VERSION 5.7 ;
BUSBITCHARS "[]" ;
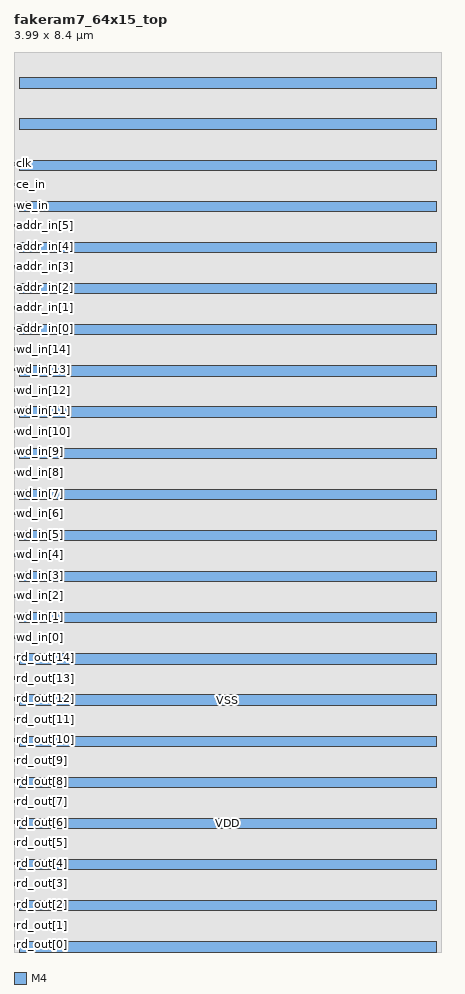
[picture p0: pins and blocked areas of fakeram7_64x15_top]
MACRO fakeram7_64x15_top
  FOREIGN fakeram7_64x15_top 0 0 ;
  SYMMETRY X Y R90 ;
  SIZE 3.990 BY 8.400 ;
  CLASS BLOCK ;
  PIN rd_out[0]
    DIRECTION OUTPUT ;
    USE SIGNAL ;
    SHAPE ABUTMENT ;
    PORT
      LAYER M4 ;
      RECT 0.000 0.048 0.024 0.072 ;
    END
  END rd_out[0]
  PIN rd_out[1]
    DIRECTION OUTPUT ;
    USE SIGNAL ;
    SHAPE ABUTMENT ;
    PORT
      LAYER M4 ;
      RECT 0.000 0.240 0.024 0.264 ;
    END
  END rd_out[1]
  PIN rd_out[2]
    DIRECTION OUTPUT ;
    USE SIGNAL ;
    SHAPE ABUTMENT ;
    PORT
      LAYER M4 ;
      RECT 0.000 0.432 0.024 0.456 ;
    END
  END rd_out[2]
  PIN rd_out[3]
    DIRECTION OUTPUT ;
    USE SIGNAL ;
    SHAPE ABUTMENT ;
    PORT
      LAYER M4 ;
      RECT 0.000 0.624 0.024 0.648 ;
    END
  END rd_out[3]
  PIN rd_out[4]
    DIRECTION OUTPUT ;
    USE SIGNAL ;
    SHAPE ABUTMENT ;
    PORT
      LAYER M4 ;
      RECT 0.000 0.816 0.024 0.840 ;
    END
  END rd_out[4]
  PIN rd_out[5]
    DIRECTION OUTPUT ;
    USE SIGNAL ;
    SHAPE ABUTMENT ;
    PORT
      LAYER M4 ;
      RECT 0.000 1.008 0.024 1.032 ;
    END
  END rd_out[5]
  PIN rd_out[6]
    DIRECTION OUTPUT ;
    USE SIGNAL ;
    SHAPE ABUTMENT ;
    PORT
      LAYER M4 ;
      RECT 0.000 1.200 0.024 1.224 ;
    END
  END rd_out[6]
  PIN rd_out[7]
    DIRECTION OUTPUT ;
    USE SIGNAL ;
    SHAPE ABUTMENT ;
    PORT
      LAYER M4 ;
      RECT 0.000 1.392 0.024 1.416 ;
    END
  END rd_out[7]
  PIN rd_out[8]
    DIRECTION OUTPUT ;
    USE SIGNAL ;
    SHAPE ABUTMENT ;
    PORT
      LAYER M4 ;
      RECT 0.000 1.584 0.024 1.608 ;
    END
  END rd_out[8]
  PIN rd_out[9]
    DIRECTION OUTPUT ;
    USE SIGNAL ;
    SHAPE ABUTMENT ;
    PORT
      LAYER M4 ;
      RECT 0.000 1.776 0.024 1.800 ;
    END
  END rd_out[9]
  PIN rd_out[10]
    DIRECTION OUTPUT ;
    USE SIGNAL ;
    SHAPE ABUTMENT ;
    PORT
      LAYER M4 ;
      RECT 0.000 1.968 0.024 1.992 ;
    END
  END rd_out[10]
  PIN rd_out[11]
    DIRECTION OUTPUT ;
    USE SIGNAL ;
    SHAPE ABUTMENT ;
    PORT
      LAYER M4 ;
      RECT 0.000 2.160 0.024 2.184 ;
    END
  END rd_out[11]
  PIN rd_out[12]
    DIRECTION OUTPUT ;
    USE SIGNAL ;
    SHAPE ABUTMENT ;
    PORT
      LAYER M4 ;
      RECT 0.000 2.352 0.024 2.376 ;
    END
  END rd_out[12]
  PIN rd_out[13]
    DIRECTION OUTPUT ;
    USE SIGNAL ;
    SHAPE ABUTMENT ;
    PORT
      LAYER M4 ;
      RECT 0.000 2.544 0.024 2.568 ;
    END
  END rd_out[13]
  PIN rd_out[14]
    DIRECTION OUTPUT ;
    USE SIGNAL ;
    SHAPE ABUTMENT ;
    PORT
      LAYER M4 ;
      RECT 0.000 2.736 0.024 2.760 ;
    END
  END rd_out[14]
  PIN wd_in[0]
    DIRECTION INPUT ;
    USE SIGNAL ;
    SHAPE ABUTMENT ;
    PORT
      LAYER M4 ;
      RECT 0.000 2.928 0.024 2.952 ;
    END
  END wd_in[0]
  PIN wd_in[1]
    DIRECTION INPUT ;
    USE SIGNAL ;
    SHAPE ABUTMENT ;
    PORT
      LAYER M4 ;
      RECT 0.000 3.120 0.024 3.144 ;
    END
  END wd_in[1]
  PIN wd_in[2]
    DIRECTION INPUT ;
    USE SIGNAL ;
    SHAPE ABUTMENT ;
    PORT
      LAYER M4 ;
      RECT 0.000 3.312 0.024 3.336 ;
    END
  END wd_in[2]
  PIN wd_in[3]
    DIRECTION INPUT ;
    USE SIGNAL ;
    SHAPE ABUTMENT ;
    PORT
      LAYER M4 ;
      RECT 0.000 3.504 0.024 3.528 ;
    END
  END wd_in[3]
  PIN wd_in[4]
    DIRECTION INPUT ;
    USE SIGNAL ;
    SHAPE ABUTMENT ;
    PORT
      LAYER M4 ;
      RECT 0.000 3.696 0.024 3.720 ;
    END
  END wd_in[4]
  PIN wd_in[5]
    DIRECTION INPUT ;
    USE SIGNAL ;
    SHAPE ABUTMENT ;
    PORT
      LAYER M4 ;
      RECT 0.000 3.888 0.024 3.912 ;
    END
  END wd_in[5]
  PIN wd_in[6]
    DIRECTION INPUT ;
    USE SIGNAL ;
    SHAPE ABUTMENT ;
    PORT
      LAYER M4 ;
      RECT 0.000 4.080 0.024 4.104 ;
    END
  END wd_in[6]
  PIN wd_in[7]
    DIRECTION INPUT ;
    USE SIGNAL ;
    SHAPE ABUTMENT ;
    PORT
      LAYER M4 ;
      RECT 0.000 4.272 0.024 4.296 ;
    END
  END wd_in[7]
  PIN wd_in[8]
    DIRECTION INPUT ;
    USE SIGNAL ;
    SHAPE ABUTMENT ;
    PORT
      LAYER M4 ;
      RECT 0.000 4.464 0.024 4.488 ;
    END
  END wd_in[8]
  PIN wd_in[9]
    DIRECTION INPUT ;
    USE SIGNAL ;
    SHAPE ABUTMENT ;
    PORT
      LAYER M4 ;
      RECT 0.000 4.656 0.024 4.680 ;
    END
  END wd_in[9]
  PIN wd_in[10]
    DIRECTION INPUT ;
    USE SIGNAL ;
    SHAPE ABUTMENT ;
    PORT
      LAYER M4 ;
      RECT 0.000 4.848 0.024 4.872 ;
    END
  END wd_in[10]
  PIN wd_in[11]
    DIRECTION INPUT ;
    USE SIGNAL ;
    SHAPE ABUTMENT ;
    PORT
      LAYER M4 ;
      RECT 0.000 5.040 0.024 5.064 ;
    END
  END wd_in[11]
  PIN wd_in[12]
    DIRECTION INPUT ;
    USE SIGNAL ;
    SHAPE ABUTMENT ;
    PORT
      LAYER M4 ;
      RECT 0.000 5.232 0.024 5.256 ;
    END
  END wd_in[12]
  PIN wd_in[13]
    DIRECTION INPUT ;
    USE SIGNAL ;
    SHAPE ABUTMENT ;
    PORT
      LAYER M4 ;
      RECT 0.000 5.424 0.024 5.448 ;
    END
  END wd_in[13]
  PIN wd_in[14]
    DIRECTION INPUT ;
    USE SIGNAL ;
    SHAPE ABUTMENT ;
    PORT
      LAYER M4 ;
      RECT 0.000 5.616 0.024 5.640 ;
    END
  END wd_in[14]
  PIN addr_in[0]
    DIRECTION INPUT ;
    USE SIGNAL ;
    SHAPE ABUTMENT ;
    PORT
      LAYER M4 ;
      RECT 0.000 5.808 0.024 5.832 ;
    END
  END addr_in[0]
  PIN addr_in[1]
    DIRECTION INPUT ;
    USE SIGNAL ;
    SHAPE ABUTMENT ;
    PORT
      LAYER M4 ;
      RECT 0.000 6.000 0.024 6.024 ;
    END
  END addr_in[1]
  PIN addr_in[2]
    DIRECTION INPUT ;
    USE SIGNAL ;
    SHAPE ABUTMENT ;
    PORT
      LAYER M4 ;
      RECT 0.000 6.192 0.024 6.216 ;
    END
  END addr_in[2]
  PIN addr_in[3]
    DIRECTION INPUT ;
    USE SIGNAL ;
    SHAPE ABUTMENT ;
    PORT
      LAYER M4 ;
      RECT 0.000 6.384 0.024 6.408 ;
    END
  END addr_in[3]
  PIN addr_in[4]
    DIRECTION INPUT ;
    USE SIGNAL ;
    SHAPE ABUTMENT ;
    PORT
      LAYER M4 ;
      RECT 0.000 6.576 0.024 6.600 ;
    END
  END addr_in[4]
  PIN addr_in[5]
    DIRECTION INPUT ;
    USE SIGNAL ;
    SHAPE ABUTMENT ;
    PORT
      LAYER M4 ;
      RECT 0.000 6.768 0.024 6.792 ;
    END
  END addr_in[5]
  PIN we_in
    DIRECTION INPUT ;
    USE SIGNAL ;
    SHAPE ABUTMENT ;
    PORT
      LAYER M4 ;
      RECT 0.000 6.960 0.024 6.984 ;
    END
  END we_in
  PIN ce_in
    DIRECTION INPUT ;
    USE SIGNAL ;
    SHAPE ABUTMENT ;
    PORT
      LAYER M4 ;
      RECT 0.000 7.152 0.024 7.176 ;
    END
  END ce_in
  PIN clk
    DIRECTION INPUT ;
    USE SIGNAL ;
    SHAPE ABUTMENT ;
    PORT
      LAYER M4 ;
      RECT 0.000 7.344 0.024 7.368 ;
    END
  END clk
  PIN VSS
    DIRECTION INOUT ;
    USE GROUND ;
    PORT
      LAYER M4 ;
      RECT 0.048 0.000 3.942 0.096 ;
      RECT 0.048 0.768 3.942 0.864 ;
      RECT 0.048 1.536 3.942 1.632 ;
      RECT 0.048 2.304 3.942 2.400 ;
      RECT 0.048 3.072 3.942 3.168 ;
      RECT 0.048 3.840 3.942 3.936 ;
      RECT 0.048 4.608 3.942 4.704 ;
      RECT 0.048 5.376 3.942 5.472 ;
      RECT 0.048 6.144 3.942 6.240 ;
      RECT 0.048 6.912 3.942 7.008 ;
      RECT 0.048 7.680 3.942 7.776 ;
    END
  END VSS
  PIN VDD
    DIRECTION INOUT ;
    USE POWER ;
    PORT
      LAYER M4 ;
      RECT 0.048 0.384 3.942 0.480 ;
      RECT 0.048 1.152 3.942 1.248 ;
      RECT 0.048 1.920 3.942 2.016 ;
      RECT 0.048 2.688 3.942 2.784 ;
      RECT 0.048 3.456 3.942 3.552 ;
      RECT 0.048 4.224 3.942 4.320 ;
      RECT 0.048 4.992 3.942 5.088 ;
      RECT 0.048 5.760 3.942 5.856 ;
      RECT 0.048 6.528 3.942 6.624 ;
      RECT 0.048 7.296 3.942 7.392 ;
      RECT 0.048 8.064 3.942 8.160 ;
    END
  END VDD
  OBS
    LAYER M1 ;
    RECT 0 0 3.990 8.400 ;
    LAYER M2 ;
    RECT 0 0 3.990 8.400 ;
    LAYER M3 ;
    RECT 0 0 3.990 8.400 ;
  END
END fakeram7_64x15_top

END LIBRARY
